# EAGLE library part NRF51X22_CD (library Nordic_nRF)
nRF51x22 For devices: nRF51422 nRF51822 Features Single chip, highly flexible, 2.4 GHz multi-protocol device 32-bit ARM Cortex M0 CPU core 256kB/128kB flash + 32kB/16kB RAM Supports Bluetooth low energy protocol stacks Thread safe and run-time protected Event driven API On air compatible with nRF24L series 3 data rates (2Mbps/1Mbps/250kbps) +4dBm output power -93dBm sensitivity, Bluetooth low energy PPI system for maximum power-efficient applications and code simplification Flexible power management system with automatic power management of each peripheral Configurable I/O mapping for analog and digital I/O Applications Mobile phone accessories Wearables Beacons Rezence wireless charging monitoring PC peripherals Consumer Electronics (CE) remote controls Proximity/Alert sensors Smart Home Sports, fitness and healthcare sensors Smart RF tags Toys and electronic games Intelligent domestic appliances Industrial and commercial sensors Lighting

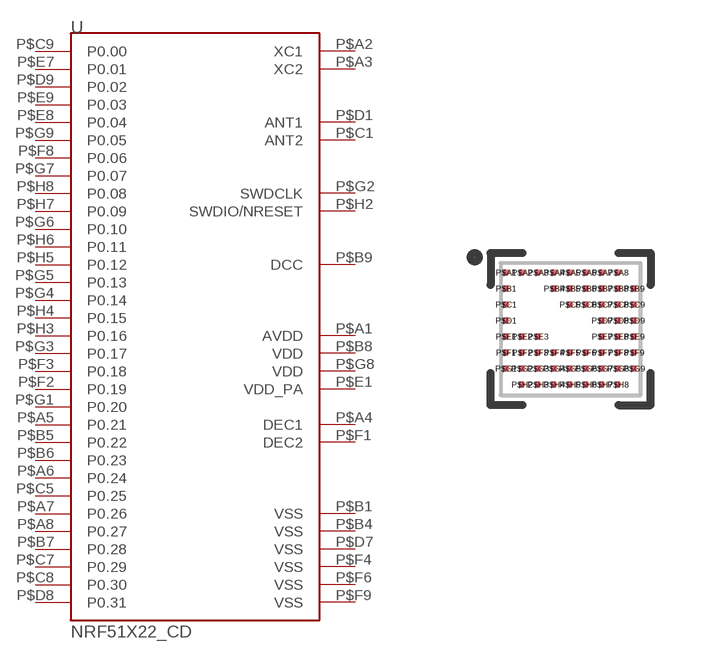
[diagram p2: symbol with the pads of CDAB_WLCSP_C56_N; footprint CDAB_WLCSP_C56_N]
Designator prefix -

## NRF51X22_CD  [CDAB_WLCSP_C56_N]
P$A1  AVDD  pwr
P$A2  XC1
P$A3  XC2
P$A4  DEC1  pwr
P$A5  P0.21
P$A6  P0.24
P$A7  P0.26
P$A8  P0.27
P$B1  VSS  pwr
P$B4  VSS  pwr
P$B5  P0.22
P$B6  P0.23
P$B7  P0.28
P$B8  VDD  pwr
P$B9  DCC  pwr
P$C1  ANT2
P$C5  P0.25
P$C7  P0.29
P$C8  P0.30
P$C9  P0.00
P$D1  ANT1
P$D7  VSS  pwr
P$D8  P0.31
P$D9  P0.02
P$E1  VDD_PA  pwr
P$E7  P0.01
P$E8  P0.04
P$E9  P0.03
P$F1  DEC2  pwr
P$F2  P0.19
P$F3  P0.18
P$F4  VSS  pwr
P$F6  VSS  pwr
P$F8  P0.06
P$F9  VSS  pwr
P$G1  P0.20
P$G2  SWDCLK  in
P$G3  P0.17
P$G4  P0.14
P$G5  P0.13
P$G6  P0.10
P$G7  P0.07
P$G8  VDD  pwr
P$G9  P0.05
P$H2  SWDIO/NRESET
P$H3  P0.16
P$H4  P0.15
P$H5  P0.12
P$H6  P0.11
P$H7  P0.09
P$H8  P0.08

## Footprint CDAB_WLCSP_C56_N (pad centres in mm)
CDAB WLCSP package
smd 0.18 x 0.18: P$A1 -1.6,1.4; P$A2 -1.2,1.4; P$A3 -0.8,1.4; P$A4 -0.4,1.4; P$A5 0,1.4; P$A6 0.4,1.4; P$A7 0.8,1.4; P$A8 1.2,1.4; P$B1 -1.6,1; P$B4 -0.4,1; P$B5 0,1; P$B6 0.4,1; P$B7 0.8,1; P$B8 1.2,1; P$B9 1.6,1; P$C1 -1.6,0.6; P$C5 0,0.6; P$C6 0.4,0.6; P$C7 0.8,0.6; P$C8 1.2,0.6; P$C9 1.6,0.6; P$D1 -1.6,0.2; P$D7 0.8,0.2; P$D8 1.2,0.2; P$D9 1.6,0.2; P$E1 -1.6,-0.2; P$E2 -1.2,-0.2; P$E3 -0.8,-0.2; P$E7 0.8,-0.2; P$E8 1.2,-0.2; P$E9 1.6,-0.2; P$F1 -1.6,-0.6; P$F2 -1.2,-0.6; P$F3 -0.8,-0.6; P$F4 -0.4,-0.6; P$F5 0,-0.6; P$F6 0.4,-0.6; P$F7 0.8,-0.6; P$F8 1.2,-0.6; P$F9 1.6,-0.6; P$G1 -1.6,-1; P$G2 -1.2,-1; P$G3 -0.8,-1; P$G4 -0.4,-1; P$G5 0,-1; P$G6 0.4,-1; P$G7 0.8,-1; P$G8 1.2,-1; P$G9 1.6,-1; P$H2 -1.2,-1.4; P$H3 -0.8,-1.4; P$H4 -0.4,-1.4; P$H5 0,-1.4; P$H6 0.4,-1.4; P$H7 0.8,-1.4; P$H8 1.2,-1.4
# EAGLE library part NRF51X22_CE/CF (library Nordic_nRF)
nRF51x22 For devices: nRF51422 nRF51822 Features Single chip, highly flexible, 2.4 GHz multi-protocol device 32-bit ARM Cortex M0 CPU core 256kB/128kB flash + 32kB/16kB RAM Supports Bluetooth low energy protocol stacks Thread safe and run-time protected Event driven API On air compatible with nRF24L series 3 data rates (2Mbps/1Mbps/250kbps) +4dBm output power -93dBm sensitivity, Bluetooth low energy PPI system for maximum power-efficient applications and code simplification Flexible power management system with automatic power management of each peripheral Configurable I/O mapping for analog and digital I/O Applications Mobile phone accessories Wearables Beacons Rezence wireless charging monitoring PC peripherals Consumer Electronics (CE) remote controls Proximity/Alert sensors Smart Home Sports, fitness and healthcare sensors Smart RF tags Toys and electronic games Intelligent domestic appliances Industrial and commercial sensors Lighting

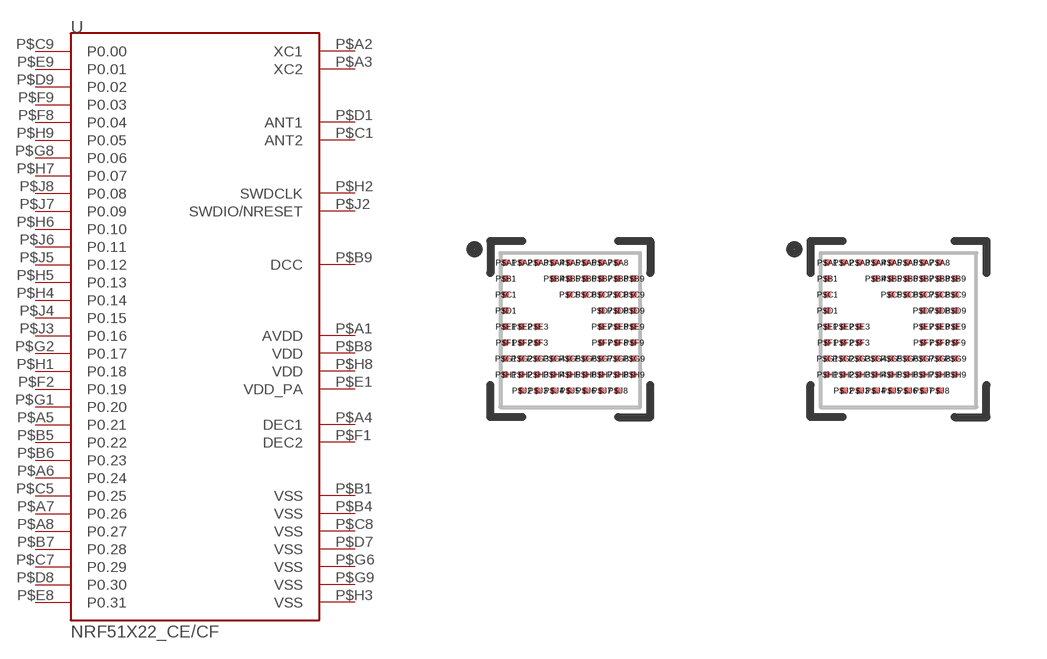
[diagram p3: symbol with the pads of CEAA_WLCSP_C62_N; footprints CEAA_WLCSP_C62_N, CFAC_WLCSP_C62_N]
Designator prefix -

## NRF51X22_CE/CFCE  [CEAA_WLCSP_C62_N]
P$A1  AVDD  pwr
P$A2  XC1
P$A3  XC2
P$A4  DEC1  pwr
P$A5  P0.21
P$A6  P0.24
P$A7  P0.26
P$A8  P0.27
P$B1  VSS  pwr
P$B4  VSS  pwr
P$B5  P0.22
P$B6  P0.23
P$B7  P0.28
P$B8  VDD  pwr
P$B9  DCC  pwr
P$C1  ANT2
P$C5  P0.25
P$C7  P0.29
P$C8  VSS  pwr
P$C9  P0.00
P$D1  ANT1
P$D7  VSS  pwr
P$D8  P0.30
P$D9  P0.02
P$E1  VDD_PA  pwr
P$E8  P0.31
P$E9  P0.01
P$F1  DEC2  pwr
P$F2  P0.19
P$F8  P0.04
P$F9  P0.03
P$G1  P0.20
P$G2  P0.17
P$G6  VSS  pwr
P$G8  P0.06
P$G9  VSS  pwr
P$H1  P0.18
P$H2  SWDCLK  in
P$H3  VSS  pwr
P$H4  P0.14
P$H5  P0.13
P$H6  P0.10
P$H7  P0.07
P$H8  VDD  pwr
P$H9  P0.05
P$J2  SWDIO/NRESET
P$J3  P0.16
P$J4  P0.15
P$J5  P0.12
P$J6  P0.11
P$J7  P0.09
P$J8  P0.08

## NRF51X22_CE/CFCF  [CFAC_WLCSP_C62_N]
Pads as for CEAA_WLCSP_C62_N

## Footprint CEAA_WLCSP_C62_N (pad centres in mm)
CEAA WLCSP package
smd 0.18 x 0.18: P$A1 -1.6,1.6; P$A2 -1.2,1.6; P$A3 -0.8,1.6; P$A4 -0.4,1.6; P$A5 0,1.6; P$A6 0.4,1.6; P$A7 0.8,1.6; P$A8 1.2,1.6; P$B1 -1.6,1.2; P$B4 -0.4,1.2; P$B5 0,1.2; P$B6 0.4,1.2; P$B7 0.8,1.2; P$B8 1.2,1.2; P$B9 1.6,1.2; P$C1 -1.6,0.8; P$C5 0,0.8; P$C6 0.4,0.8; P$C7 0.8,0.8; P$C8 1.2,0.8; P$C9 1.6,0.8; P$D1 -1.6,0.4; P$D7 0.8,0.4; P$D8 1.2,0.4; P$D9 1.6,0.4; P$E1 -1.6,0; P$E2 -1.2,0; P$E3 -0.8,0; P$E7 0.8,0; P$E8 1.2,0; P$E9 1.6,0; P$F1 -1.6,-0.4; P$F2 -1.2,-0.4; P$F3 -0.8,-0.4; P$F7 0.8,-0.4; P$F8 1.2,-0.4; P$F9 1.6,-0.4; P$G1 -1.6,-0.8; P$G2 -1.2,-0.8; P$G3 -0.8,-0.8; P$G4 -0.4,-0.8; P$G5 0,-0.8; P$G6 0.4,-0.8; P$G7 0.8,-0.8; P$G8 1.2,-0.8; P$G9 1.6,-0.8; P$H1 -1.6,-1.2; P$H2 -1.2,-1.2; P$H3 -0.8,-1.2; P$H4 -0.4,-1.2; P$H5 0,-1.2; P$H6 0.4,-1.2; P$H7 0.8,-1.2; P$H8 1.2,-1.2; P$H9 1.6,-1.2; P$J2 -1.2,-1.6; P$J3 -0.8,-1.6; P$J4 -0.4,-1.6; P$J5 0,-1.6; P$J6 0.4,-1.6; P$J7 0.8,-1.6; P$J8 1.2,-1.6

## Footprint CFAC_WLCSP_C62_N (pad centres in mm)
CEAA WLCSP package
smd 0.18 x 0.18: P$A1 -1.6,1.6; P$A2 -1.2,1.6; P$A3 -0.8,1.6; P$A4 -0.4,1.6; P$A5 0,1.6; P$A6 0.4,1.6; P$A7 0.8,1.6; P$A8 1.2,1.6; P$B1 -1.6,1.2; P$B4 -0.4,1.2; P$B5 0,1.2; P$B6 0.4,1.2; P$B7 0.8,1.2; P$B8 1.2,1.2; P$B9 1.6,1.2; P$C1 -1.6,0.8; P$C5 0,0.8; P$C6 0.4,0.8; P$C7 0.8,0.8; P$C8 1.2,0.8; P$C9 1.6,0.8; P$D1 -1.6,0.4; P$D7 0.8,0.4; P$D8 1.2,0.4; P$D9 1.6,0.4; P$E1 -1.6,0; P$E2 -1.2,0; P$E3 -0.8,0; P$E7 0.8,0; P$E8 1.2,0; P$E9 1.6,0; P$F1 -1.6,-0.4; P$F2 -1.2,-0.4; P$F3 -0.8,-0.4; P$F7 0.8,-0.4; P$F8 1.2,-0.4; P$F9 1.6,-0.4; P$G1 -1.6,-0.8; P$G2 -1.2,-0.8; P$G3 -0.8,-0.8; P$G4 -0.4,-0.8; P$G5 0,-0.8; P$G6 0.4,-0.8; P$G7 0.8,-0.8; P$G8 1.2,-0.8; P$G9 1.6,-0.8; P$H1 -1.6,-1.2; P$H2 -1.2,-1.2; P$H3 -0.8,-1.2; P$H4 -0.4,-1.2; P$H5 0,-1.2; P$H6 0.4,-1.2; P$H7 0.8,-1.2; P$H8 1.2,-1.2; P$H9 1.6,-1.2; P$J2 -1.2,-1.6; P$J3 -0.8,-1.6; P$J4 -0.4,-1.6; P$J5 0,-1.6; P$J6 0.4,-1.6; P$J7 0.8,-1.6; P$J8 1.2,-1.6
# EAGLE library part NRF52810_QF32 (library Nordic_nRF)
nRF52810 Features Single chip, highly flexible, 2.4 GHz multi-protocol SoC 32-bit ARM Cortex-M4 Processor 1.7v to 3.6v operation 192kB flash + 24kB RAM Supports concurrent Bluetooth low energy/ANT protocol operation Up to +4dBm output power -96dBm sensitivity, Bluetooth low energy Thread safe and run-time protected Event driven API On air compatible with nRF24L and nRF24AP series 2 data rates (2Mbps/1Mbps) PPI - maximum flexibility for power-efficient applications and code simplification Automated power management system with automatic power management of each peripheral Configurable I/O mapping for analog and digital I/O 1 x Master/Slave SPI 1 x Two-wire interface (I²C) UART (RTS/CTS) 1 x PWM (4 channels) AES HW encryption 8-channel 10/12-bit ADC Quadrature decoder 64-level analog comparator Real Time Counter (RTC) Digital microphone interface (PDM) On-chip balun Applications Bluetooth 5 connectivity processor Industrial sensors and actuators Wearables SmartHome sensors computer peripherals RF smart remotes Airfuel (A4WP) wireless charging Beacons Sports and fitness sensors Connected health products Smart watches RC Toys Interactive games Building automation

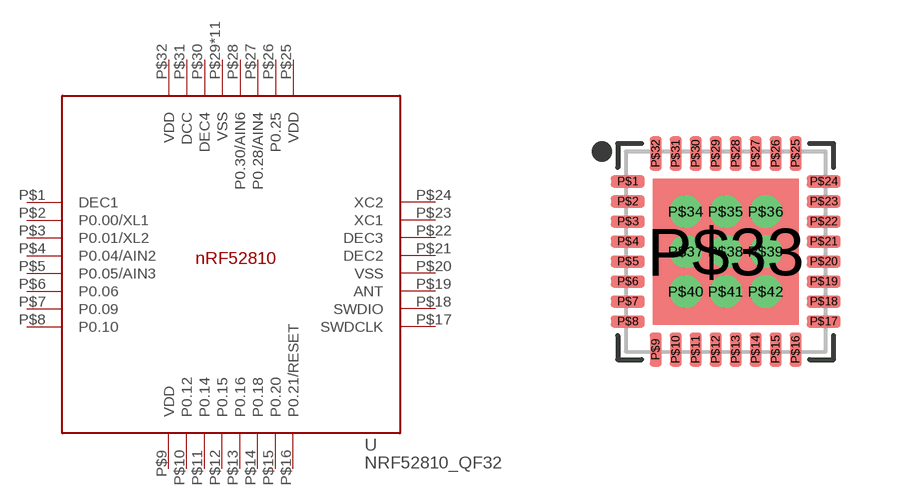
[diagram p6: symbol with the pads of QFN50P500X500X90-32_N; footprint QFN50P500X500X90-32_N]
Designator prefix -

## NRF52810_QF32  [QFN50P500X500X90-32_N]
P$1  DEC1
P$2  P0.00/XL1
P$3  P0.01/XL2
P$4  P0.04/AIN2
P$5  P0.05/AIN3
P$6  P0.06
P$7  P0.09
P$8  P0.10
P$9  VDD
P$10  P0.12
P$11  P0.14
P$12  P0.15
P$13  P0.16
P$14  P0.18
P$15  P0.20
P$16  P0.21/RESET
P$17  SWDCLK
P$18  SWDIO
P$19  ANT
P$20  VSS
P$21  DEC2
P$22  DEC3
P$23  XC1
P$24  XC2
P$25  VDD
P$26  P0.25
P$27  P0.28/AIN4
P$28  P0.30/AIN6
P$29  VSS
P$30  DEC4
P$31  DCC
P$32  VDD
P$33  VSS
P$34  VSS
P$35  VSS
P$36  VSS
P$37  VSS
P$38  VSS
P$39  VSS
P$40  VSS
P$41  VSS
P$42  VSS

## Footprint QFN50P500X500X90-32_N (pad centres in mm)
smd 0.85 x 0.3: P$1 -2.45,1.75; P$2 -2.45,1.25; P$3 -2.45,0.75; P$4 -2.45,0.25; P$5 -2.45,-0.25; P$6 -2.45,-0.75; P$7 -2.45,-1.25; P$8 -2.45,-1.75; P$17 2.45,-1.75; P$18 2.45,-1.25; P$19 2.45,-0.75; P$20 2.45,-0.25; P$21 2.45,0.25; P$22 2.45,0.75; P$23 2.45,1.25; P$24 2.45,1.75
smd 0.3 x 0.85: P$9 -1.75,-2.45; P$10 -1.25,-2.45; P$11 -0.75,-2.45; P$12 -0.25,-2.45; P$13 0.25,-2.45; P$14 0.75,-2.45; P$15 1.25,-2.45; P$16 1.75,-2.45; P$25 1.75,2.45; P$26 1.25,2.45; P$27 0.75,2.45; P$28 0.25,2.45; P$29 -0.25,2.45; P$30 -0.75,2.45; P$31 -1.25,2.45; P$32 -1.75,2.45
smd 3.65 x 3.65: P$33 0,0
drill 0.3 pad 0.6: P$34 -1,1; P$35 0,1; P$36 1,1; P$37 -1,0; P$38 0,0; P$39 1,0; P$40 -1,-1; P$41 0,-1; P$42 1,-1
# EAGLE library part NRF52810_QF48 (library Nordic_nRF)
nRF52810 Features Single chip, highly flexible, 2.4 GHz multi-protocol SoC 32-bit ARM Cortex-M4 Processor 1.7v to 3.6v operation 192kB flash + 24kB RAM Supports concurrent Bluetooth low energy/ANT protocol operation Up to +4dBm output power -96dBm sensitivity, Bluetooth low energy Thread safe and run-time protected Event driven API On air compatible with nRF24L and nRF24AP series 2 data rates (2Mbps/1Mbps) PPI - maximum flexibility for power-efficient applications and code simplification Automated power management system with automatic power management of each peripheral Configurable I/O mapping for analog and digital I/O 1 x Master/Slave SPI 1 x Two-wire interface (I²C) UART (RTS/CTS) 1 x PWM (4 channels) AES HW encryption 8-channel 10/12-bit ADC Quadrature decoder 64-level analog comparator Real Time Counter (RTC) Digital microphone interface (PDM) On-chip balun Applications Bluetooth 5 connectivity processor Industrial sensors and actuators Wearables SmartHome sensors computer peripherals RF smart remotes Airfuel (A4WP) wireless charging Beacons Sports and fitness sensors Connected health products Smart watches RC Toys Interactive games Building automation

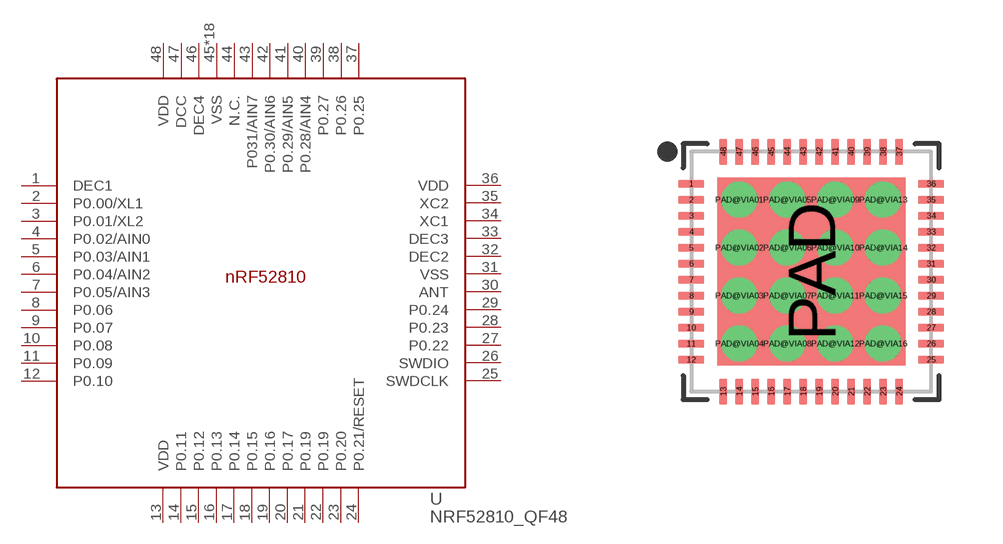
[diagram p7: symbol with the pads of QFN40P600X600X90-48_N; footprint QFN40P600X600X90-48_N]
Designator prefix -

## NRF52810_QF48  [QFN40P600X600X90-48_N]
1  DEC1
2  P0.00/XL1
3  P0.01/XL2
4  P0.02/AIN0
5  P0.03/AIN1
6  P0.04/AIN2
7  P0.05/AIN3
8  P0.06
9  P0.07
10  P0.08
11  P0.09
12  P0.10
13  VDD
14  P0.11
15  P0.12
16  P0.13
17  P0.14
18  P0.15
19  P0.16
20  P0.17
21  P0.19
22  P0.19
23  P0.20
24  P0.21/RESET
25  SWDCLK
26  SWDIO
27  P0.22
28  P0.23
29  P0.24
30  ANT
31  VSS
32  DEC2
33  DEC3
34  XC1
35  XC2
36  VDD
37  P0.25
38  P0.26
39  P0.27
40  P0.28/AIN4
41  P0.29/AIN5
42  P0.30/AIN6
43  P031/AIN7
44  N.C.
45  VSS
46  DEC4
47  DCC
48  VDD
PAD  VSS
PAD@VIA01  VSS
PAD@VIA02  VSS
PAD@VIA03  VSS
PAD@VIA04  VSS
PAD@VIA05  VSS
PAD@VIA06  VSS
PAD@VIA07  VSS
PAD@VIA08  VSS
PAD@VIA09  VSS
PAD@VIA10  VSS
PAD@VIA11  VSS
PAD@VIA12  VSS
PAD@VIA13  VSS
PAD@VIA14  VSS
PAD@VIA15  VSS
PAD@VIA16  VSS

## Footprint QFN40P600X600X90-48_N (pad centres in mm)
QFN40P600X600X90-48N QFN, 48-Leads Body 6.0x6.0mm (max) Pitch 0.40mm IPC Medium Density
smd 0.65 x 0.2: 1 -3,2.2; 2 -3,1.8; 3 -3,1.4; 4 -3,1; 5 -3,0.6; 6 -3,0.2; 7 -3,-0.2; 8 -3,-0.6; 9 -3,-1; 10 -3,-1.4; 11 -3,-1.8; 12 -3,-2.2; 25 3,-2.2; 26 3,-1.8; 27 3,-1.4; 28 3,-1; 29 3,-0.6; 30 3,-0.2; 31 3,0.2; 32 3,0.6; 33 3,1; 34 3,1.4; 35 3,1.8; 36 3,2.2
smd 0.2 x 0.65: 13 -2.2,-3; 14 -1.8,-3; 15 -1.4,-3; 16 -1,-3; 17 -0.6,-3; 18 -0.2,-3; 19 0.2,-3; 20 0.6,-3; 21 1,-3; 22 1.4,-3; 23 1.8,-3; 24 2.2,-3; 37 2.2,3; 38 1.8,3; 39 1.4,3; 40 1,3; 41 0.6,3; 42 0.2,3; 43 -0.2,3; 44 -0.6,3; 45 -1,3; 46 -1.4,3; 47 -1.8,3; 48 -2.2,3
smd 4.7 x 4.7: PAD 0,0
drill 0.4: PAD@VIA01 -1.8,1.8; PAD@VIA02 -1.8,0.6; PAD@VIA03 -1.8,-0.6; PAD@VIA04 -1.8,-1.8; PAD@VIA05 -0.6,1.8; PAD@VIA06 -0.6,0.6; PAD@VIA07 -0.6,-0.6; PAD@VIA08 -0.6,-1.8; PAD@VIA09 0.6,1.8; PAD@VIA10 0.6,0.6; PAD@VIA11 0.6,-0.6; PAD@VIA12 0.6,-1.8; PAD@VIA13 1.8,1.8; PAD@VIA14 1.8,0.6; PAD@VIA15 1.8,-0.6; PAD@VIA16 1.8,-1.8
